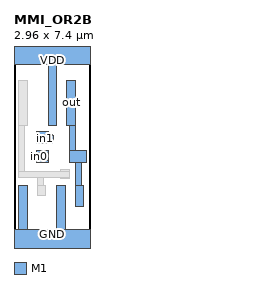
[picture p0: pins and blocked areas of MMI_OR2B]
MACRO MMI_OR2B
	CLASS CORE ;
	FOREIGN MMI_OR2B 0 0 ;
	SIZE 2.96 BY 7.4 ;
	SYMMETRY X Y ;
	SITE CORE1 ;
	PIN out
		DIRECTION output ;
		USE SIGNAL ;
		PORT
			LAYER M1 ;
			RECT 2.05 4.545 2.39 6.305 ;
			LAYER M1 ;
			RECT 2.16 3.555 2.39 4.545 ;
			LAYER M1 ;
			RECT 2.16 3.105 2.815 3.555 ;
			LAYER M1 ;
			RECT 2.38 2.21 2.61 3.105 ;
			LAYER M1 ;
			RECT 2.38 1.37 2.72 2.21 ;
		END
		AntennaDiffArea 1.3248 ;
	END out
	PIN in1
		DIRECTION input ;
		USE SIGNAL ;
		PORT
			LAYER M1 ;
			RECT 0.885 4.19 1.335 4.295 ;
			LAYER M1 ;
			RECT 0.885 4.135 1.48 4.19 ;
			LAYER M1 ;
			RECT 0.885 3.905 1.545 4.135 ;
			LAYER M1 ;
			RECT 0.885 3.85 1.48 3.905 ;
			LAYER M1 ;
			RECT 0.885 3.845 1.335 3.85 ;
		END
		AntennaGateArea 0.414 ;
	END in1
	PIN GND
		DIRECTION inout ;
		USE GROUND ;
		PORT
			LAYER M1 ;
			RECT 0.18 0.5 0.52 2.21 ;
			LAYER M1 ;
			RECT 1.66 0.5 2 2.21 ;
			LAYER M1 ;
			RECT 0 -0.5 2.96 0.5 ;
		END
	END GND
	PIN VDD
		DIRECTION inout ;
		USE POWER ;
		PORT
			LAYER M1 ;
			RECT 0 6.9 2.96 7.9 ;
			LAYER M1 ;
			RECT 1.33 4.545 1.67 6.9 ;
		END
	END VDD
	PIN in0
		DIRECTION input ;
		USE SIGNAL ;
		PORT
			LAYER M1 ;
			RECT 0.885 3.5 1.335 3.555 ;
			LAYER M1 ;
			RECT 0.64 3.16 1.335 3.5 ;
			LAYER M1 ;
			RECT 0.885 3.105 1.335 3.16 ;
		END
		AntennaGateArea 0.414 ;
	END in0
	OBS
		LAYER M1 ;
		RECT 0.18 4.545 0.52 6.305 ;
		LAYER M1 ;
		RECT 0.18 2.755 0.41 4.545 ;
		LAYER M1 ;
		RECT 1.81 2.755 2.15 2.81 ;
		LAYER M1 ;
		RECT 0.18 2.525 2.15 2.755 ;
		LAYER M1 ;
		RECT 0.9 2.21 1.13 2.525 ;
		LAYER M1 ;
		RECT 1.81 2.47 2.15 2.525 ;
		LAYER M1 ;
		RECT 0.9 1.83 1.24 2.21 ;
	END
END MMI_OR2B
